VERSION 5.4 ;
NAMESCASESENSITIVE ON ;
BUSBITCHARS "[]" ;
DIVIDERCHAR "/" ;
UNITS
  DATABASE MICRONS 2000 ;
END UNITS
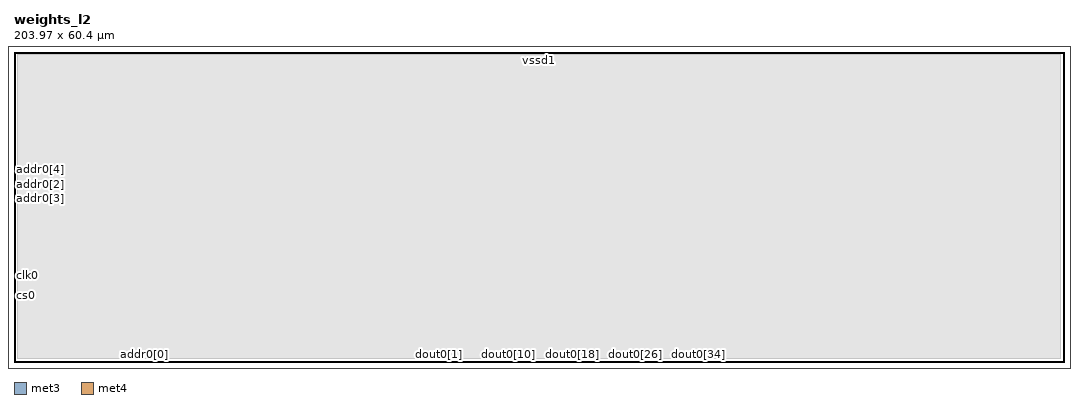
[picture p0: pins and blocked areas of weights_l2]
MACRO weights_l2
   CLASS BLOCK ;
   SIZE 203.97 BY 60.4 ;
   SYMMETRY X Y R90 ;
   PIN clk0
      DIRECTION INPUT ;
      PORT
         LAYER met3 ;
         RECT  -7.48 16.69 -7.1 17.07 ;
      END
   END clk0
   PIN cs0
      DIRECTION INPUT ;
      PORT
         LAYER met3 ;
         RECT  -7.48 12.675 -7.1 13.055 ;
      END
   END cs0
   PIN addr0[0]
      DIRECTION INPUT ;
      PORT
         LAYER met4 ;
         RECT  25.11 -7.48 25.49 -7.1 ;
      END
   END addr0[0]
   PIN addr0[1]
      DIRECTION INPUT ;
      PORT
         LAYER met4 ;
         RECT  27.15 -7.48 27.53 -7.1 ;
      END
   END addr0[1]
   PIN addr0[2]
      DIRECTION INPUT ;
      PORT
         LAYER met3 ;
         RECT  -7.48 34.31 -7.1 34.69 ;
      END
   END addr0[2]
   PIN addr0[3]
      DIRECTION INPUT ;
      PORT
         LAYER met3 ;
         RECT  -7.48 32.84 -7.1 33.22 ;
      END
   END addr0[3]
   PIN addr0[4]
      DIRECTION INPUT ;
      PORT
         LAYER met3 ;
         RECT  -7.48 35.795 -7.1 36.175 ;
      END
   END addr0[4]
   PIN dout0[0]
      DIRECTION OUTPUT ;
      PORT
         LAYER met4 ;
         RECT  81.6 -7.48 81.98 -7.1 ;
      END
   END dout0[0]
   PIN dout0[1]
      DIRECTION OUTPUT ;
      PORT
         LAYER met4 ;
         RECT  82.29 -7.48 82.67 -7.1 ;
      END
   END dout0[1]
   PIN dout0[2]
      DIRECTION OUTPUT ;
      PORT
         LAYER met4 ;
         RECT  83.595 -7.48 83.975 -7.1 ;
      END
   END dout0[2]
   PIN dout0[3]
      DIRECTION OUTPUT ;
      PORT
         LAYER met4 ;
         RECT  85.135 -7.48 85.515 -7.1 ;
      END
   END dout0[3]
   PIN dout0[4]
      DIRECTION OUTPUT ;
      PORT
         LAYER met4 ;
         RECT  86.675 -7.48 87.055 -7.1 ;
      END
   END dout0[4]
   PIN dout0[5]
      DIRECTION OUTPUT ;
      PORT
         LAYER met4 ;
         RECT  88.215 -7.48 88.595 -7.1 ;
      END
   END dout0[5]
   PIN dout0[6]
      DIRECTION OUTPUT ;
      PORT
         LAYER met4 ;
         RECT  89.755 -7.48 90.135 -7.1 ;
      END
   END dout0[6]
   PIN dout0[7]
      DIRECTION OUTPUT ;
      PORT
         LAYER met4 ;
         RECT  91.295 -7.48 91.675 -7.1 ;
      END
   END dout0[7]
   PIN dout0[8]
      DIRECTION OUTPUT ;
      PORT
         LAYER met4 ;
         RECT  92.835 -7.48 93.215 -7.1 ;
      END
   END dout0[8]
   PIN dout0[9]
      DIRECTION OUTPUT ;
      PORT
         LAYER met4 ;
         RECT  94.375 -7.48 94.755 -7.1 ;
      END
   END dout0[9]
   PIN dout0[10]
      DIRECTION OUTPUT ;
      PORT
         LAYER met4 ;
         RECT  95.915 -7.48 96.295 -7.1 ;
      END
   END dout0[10]
   PIN dout0[11]
      DIRECTION OUTPUT ;
      PORT
         LAYER met4 ;
         RECT  97.455 -7.48 97.835 -7.1 ;
      END
   END dout0[11]
   PIN dout0[12]
      DIRECTION OUTPUT ;
      PORT
         LAYER met4 ;
         RECT  98.995 -7.48 99.375 -7.1 ;
      END
   END dout0[12]
   PIN dout0[13]
      DIRECTION OUTPUT ;
      PORT
         LAYER met4 ;
         RECT  100.535 -7.48 100.915 -7.1 ;
      END
   END dout0[13]
   PIN dout0[14]
      DIRECTION OUTPUT ;
      PORT
         LAYER met4 ;
         RECT  102.075 -7.48 102.455 -7.1 ;
      END
   END dout0[14]
   PIN dout0[15]
      DIRECTION OUTPUT ;
      PORT
         LAYER met4 ;
         RECT  103.615 -7.48 103.995 -7.1 ;
      END
   END dout0[15]
   PIN dout0[16]
      DIRECTION OUTPUT ;
      PORT
         LAYER met4 ;
         RECT  105.155 -7.48 105.535 -7.1 ;
      END
   END dout0[16]
   PIN dout0[17]
      DIRECTION OUTPUT ;
      PORT
         LAYER met4 ;
         RECT  106.695 -7.48 107.075 -7.1 ;
      END
   END dout0[17]
   PIN dout0[18]
      DIRECTION OUTPUT ;
      PORT
         LAYER met4 ;
         RECT  108.235 -7.48 108.615 -7.1 ;
      END
   END dout0[18]
   PIN dout0[19]
      DIRECTION OUTPUT ;
      PORT
         LAYER met4 ;
         RECT  109.775 -7.48 110.155 -7.1 ;
      END
   END dout0[19]
   PIN dout0[20]
      DIRECTION OUTPUT ;
      PORT
         LAYER met4 ;
         RECT  111.315 -7.48 111.695 -7.1 ;
      END
   END dout0[20]
   PIN dout0[21]
      DIRECTION OUTPUT ;
      PORT
         LAYER met4 ;
         RECT  112.855 -7.48 113.235 -7.1 ;
      END
   END dout0[21]
   PIN dout0[22]
      DIRECTION OUTPUT ;
      PORT
         LAYER met4 ;
         RECT  114.395 -7.48 114.775 -7.1 ;
      END
   END dout0[22]
   PIN dout0[23]
      DIRECTION OUTPUT ;
      PORT
         LAYER met4 ;
         RECT  115.935 -7.48 116.315 -7.1 ;
      END
   END dout0[23]
   PIN dout0[24]
      DIRECTION OUTPUT ;
      PORT
         LAYER met4 ;
         RECT  117.475 -7.48 117.855 -7.1 ;
      END
   END dout0[24]
   PIN dout0[25]
      DIRECTION OUTPUT ;
      PORT
         LAYER met4 ;
         RECT  119.015 -7.48 119.395 -7.1 ;
      END
   END dout0[25]
   PIN dout0[26]
      DIRECTION OUTPUT ;
      PORT
         LAYER met4 ;
         RECT  120.555 -7.48 120.935 -7.1 ;
      END
   END dout0[26]
   PIN dout0[27]
      DIRECTION OUTPUT ;
      PORT
         LAYER met4 ;
         RECT  121.99 -7.48 122.37 -7.1 ;
      END
   END dout0[27]
   PIN dout0[28]
      DIRECTION OUTPUT ;
      PORT
         LAYER met4 ;
         RECT  124.38 -7.48 124.76 -7.1 ;
      END
   END dout0[28]
   PIN dout0[29]
      DIRECTION OUTPUT ;
      PORT
         LAYER met4 ;
         RECT  125.175 -7.48 125.555 -7.1 ;
      END
   END dout0[29]
   PIN dout0[30]
      DIRECTION OUTPUT ;
      PORT
         LAYER met4 ;
         RECT  126.715 -7.48 127.095 -7.1 ;
      END
   END dout0[30]
   PIN dout0[31]
      DIRECTION OUTPUT ;
      PORT
         LAYER met4 ;
         RECT  128.255 -7.48 128.635 -7.1 ;
      END
   END dout0[31]
   PIN dout0[32]
      DIRECTION OUTPUT ;
      PORT
         LAYER met4 ;
         RECT  129.795 -7.48 130.175 -7.1 ;
      END
   END dout0[32]
   PIN dout0[33]
      DIRECTION OUTPUT ;
      PORT
         LAYER met4 ;
         RECT  131.335 -7.48 131.715 -7.1 ;
      END
   END dout0[33]
   PIN dout0[34]
      DIRECTION OUTPUT ;
      PORT
         LAYER met4 ;
         RECT  132.875 -7.48 133.255 -7.1 ;
      END
   END dout0[34]
   PIN dout0[35]
      DIRECTION OUTPUT ;
      PORT
         LAYER met4 ;
         RECT  134.415 -7.48 134.795 -7.1 ;
      END
   END dout0[35]
   PIN dout0[36]
      DIRECTION OUTPUT ;
      PORT
         LAYER met4 ;
         RECT  135.955 -7.48 136.335 -7.1 ;
      END
   END dout0[36]
   PIN dout0[37]
      DIRECTION OUTPUT ;
      PORT
         LAYER met4 ;
         RECT  137.495 -7.48 137.875 -7.1 ;
      END
   END dout0[37]
   PIN dout0[38]
      DIRECTION OUTPUT ;
      PORT
         LAYER met4 ;
         RECT  139.035 -7.48 139.415 -7.1 ;
      END
   END dout0[38]
   PIN dout0[39]
      DIRECTION OUTPUT ;
      PORT
         LAYER met4 ;
         RECT  140.485 -7.48 140.865 -7.1 ;
      END
   END dout0[39]
   PIN vccd1
      DIRECTION INOUT ;
      USE POWER ; 
      SHAPE ABUTMENT ; 
      PORT
         LAYER met4 ;
         RECT  209.71 -7.48 211.45 67.88 ;
         LAYER met3 ;
         RECT  -7.48 -7.48 211.45 -5.74 ;
         LAYER met3 ;
         RECT  -7.48 66.14 211.45 67.88 ;
         LAYER met4 ;
         RECT  -7.48 -7.48 -5.74 67.88 ;
      END
   END vccd1
   PIN vssd1
      DIRECTION INOUT ;
      USE GROUND ; 
      SHAPE ABUTMENT ; 
      PORT
         LAYER met4 ;
         RECT  -4.0 -4.0 -2.26 64.4 ;
         LAYER met4 ;
         RECT  206.23 -4.0 207.97 64.4 ;
         LAYER met3 ;
         RECT  -4.0 -4.0 207.97 -2.26 ;
         LAYER met3 ;
         RECT  -4.0 62.66 207.97 64.4 ;
      END
   END vssd1
   OBS
   LAYER  met1 ;
      RECT  0.62 0.62 203.35 59.78 ;
   LAYER  met2 ;
      RECT  0.62 0.62 203.35 59.78 ;
   LAYER  met3 ;
      RECT  0.62 0.62 203.35 59.78 ;
   LAYER  met4 ;
      RECT  0.62 0.62 203.35 59.78 ;
   END
END    weights_l2
END    LIBRARY
